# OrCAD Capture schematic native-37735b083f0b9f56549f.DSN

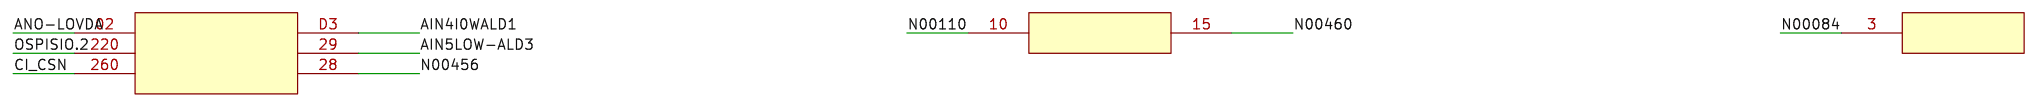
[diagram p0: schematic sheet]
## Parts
P0  CONNECTOR
P1  CONNECTOR
P11  CONNECTOR

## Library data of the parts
P0 = OBS_P0
P1 = OBS_P1
P11 = OBS_P11

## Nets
AIN4I0WALD1: P0.D3
AIN5LOW-ALD3: P0.29
ANO-LOVDA: P0.02
CI_CSN: P0.260
OSPISIO.2: P0.220

Not connected (* = marked no-connect by the designer): P0 28; P1 10 15; P11 3
